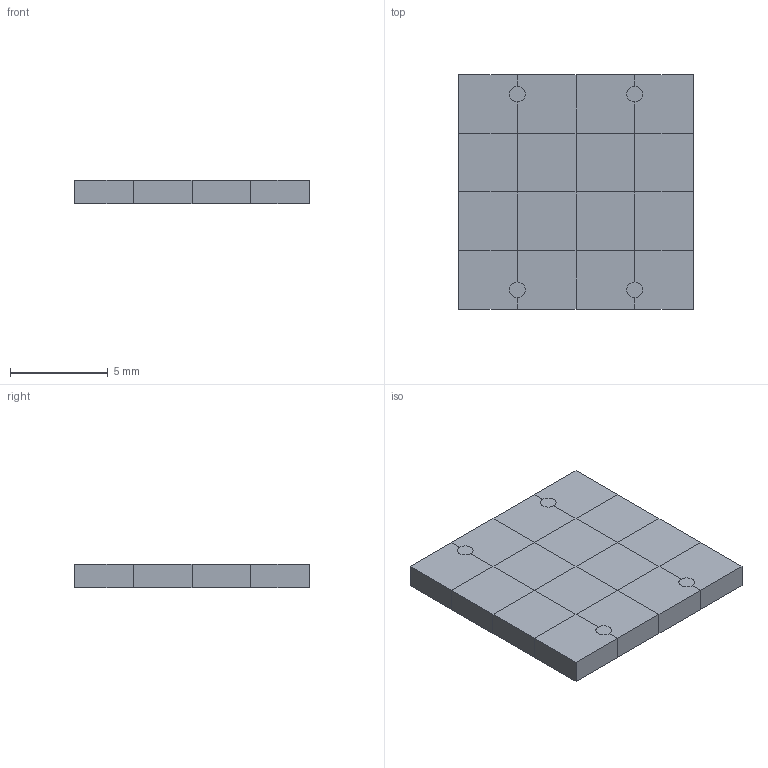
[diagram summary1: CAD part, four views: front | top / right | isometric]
STEP (ISO 10303-21) file: header records copied from the file, then geometry measured from it (millimetres).
FILE_DESCRIPTION(('Open CASCADE Model'),'2;1');
FILE_NAME('Open CASCADE Shape Model','2026-11-27T10:08:37',('Author'),( 'Open CASCADE'),'Open CASCADE STEP processor 7.9','Open CASCADE 7.9' ,'Unknown');
FILE_SCHEMA(('AUTOMOTIVE_DESIGN { 1 0 10303 214 1 1 1 1 }'));
Length unit declared in the file: millimetre
Products named in the file (3): manifold_N19; fluid; solid
Assembly tree (2 placements, depth 2):
  manifold_N19
    fluid
    solid
Bounding box: 12 x 12 x 1.2 mm (x, y, z)
Volume: 172.8 mm3; surface area: 1483.2 mm2
Topology: 2 solids, 2 shells, 1612 faces, 5792 edges, 3214 vertices
Faces by surface type: plane 1604, cylinder 8
Full cylindrical faces by diameter (mm): 0.8 x8
Entity records: 135398 total; most frequent: CARTESIAN_POINT 22253, DIRECTION 20622, LINE 17328, VECTOR 17328, ORIENTED_EDGE 11584, PCURVE 11584, DEFINITIONAL_REPRESENTATION 11584, EDGE_CURVE 5792
One B-rep face of a CAD part: STEP entity #72610.
In plain terms, the planar face has unit normal (0, 0, 1).
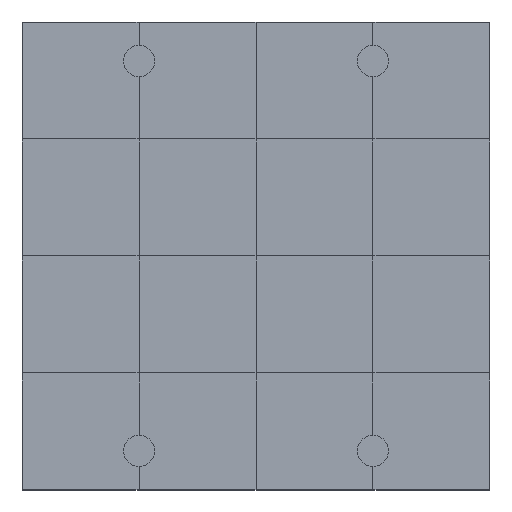
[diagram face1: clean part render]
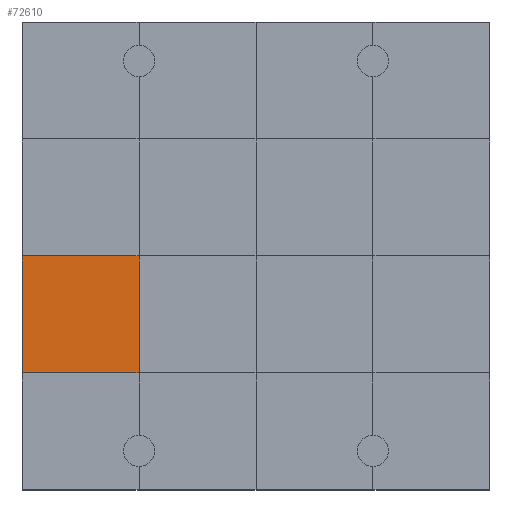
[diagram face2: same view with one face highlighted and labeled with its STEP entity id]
Its self-contained STEP definition (entity closure, numbers rounded to 3 decimals):
#72160 = VERTEX_POINT('',#72161);
#72161 = CARTESIAN_POINT('',(0.,3.,1.2));
#72175 = PLANE('',#72176);
#72176 = AXIS2_PLACEMENT_3D('',#72177,#72178,#72179);
#72177 = CARTESIAN_POINT('',(0.,3.,0.));
#72178 = DIRECTION('',(1.,0.,-0.));
#72179 = DIRECTION('',(0.,0.,1.));
#72201 = PLANE('',#72202);
#72202 = AXIS2_PLACEMENT_3D('',#72203,#72204,#72205);
#72203 = CARTESIAN_POINT('',(0.,0.,1.2));
#72204 = DIRECTION('',(0.,0.,1.));
#72205 = DIRECTION('',(1.,0.,-0.));
#72352 = VERTEX_POINT('',#72353);
#72353 = CARTESIAN_POINT('',(3.,3.,1.2));
#72374 = EDGE_CURVE('',#72160,#72352,#72375,.T.);
#72375 = SURFACE_CURVE('',#72376,(#72380,#72387),.PCURVE_S1.);
#72376 = LINE('',#72377,#72378);
#72377 = CARTESIAN_POINT('',(0.,3.,1.2));
#72378 = VECTOR('',#72379,1.);
#72379 = DIRECTION('',(1.,0.,-0.));
#72380 = PCURVE('',#72201,#72381);
#72381 = DEFINITIONAL_REPRESENTATION('',(#72382),#72386);
#72382 = LINE('',#72383,#72384);
#72383 = CARTESIAN_POINT('',(0.,3.));
#72384 = VECTOR('',#72385,1.);
#72385 = DIRECTION('',(1.,0.));
#72386 = ( GEOMETRIC_REPRESENTATION_CONTEXT(2) 
PARAMETRIC_REPRESENTATION_CONTEXT() REPRESENTATION_CONTEXT('2D SPACE',''
  ) );
#72387 = PCURVE('',#72388,#72393);
#72388 = PLANE('',#72389);
#72389 = AXIS2_PLACEMENT_3D('',#72390,#72391,#72392);
#72390 = CARTESIAN_POINT('',(0.,3.,1.2));
#72391 = DIRECTION('',(0.,0.,1.));
#72392 = DIRECTION('',(1.,0.,-0.));
#72393 = DEFINITIONAL_REPRESENTATION('',(#72394),#72398);
#72394 = LINE('',#72395,#72396);
#72395 = CARTESIAN_POINT('',(0.,0.));
#72396 = VECTOR('',#72397,1.);
#72397 = DIRECTION('',(1.,0.));
#72398 = ( GEOMETRIC_REPRESENTATION_CONTEXT(2) 
PARAMETRIC_REPRESENTATION_CONTEXT() REPRESENTATION_CONTEXT('2D SPACE',''
  ) );
#72433 = VERTEX_POINT('',#72434);
#72434 = CARTESIAN_POINT('',(0.,6.,1.2));
#72460 = EDGE_CURVE('',#72160,#72433,#72461,.T.);
#72461 = SURFACE_CURVE('',#72462,(#72466,#72473),.PCURVE_S1.);
#72462 = LINE('',#72463,#72464);
#72463 = CARTESIAN_POINT('',(0.,3.,1.2));
#72464 = VECTOR('',#72465,1.);
#72465 = DIRECTION('',(-0.,1.,0.));
#72466 = PCURVE('',#72175,#72467);
#72467 = DEFINITIONAL_REPRESENTATION('',(#72468),#72472);
#72468 = LINE('',#72469,#72470);
#72469 = CARTESIAN_POINT('',(1.2,0.));
#72470 = VECTOR('',#72471,1.);
#72471 = DIRECTION('',(0.,-1.));
#72472 = ( GEOMETRIC_REPRESENTATION_CONTEXT(2) 
PARAMETRIC_REPRESENTATION_CONTEXT() REPRESENTATION_CONTEXT('2D SPACE',''
  ) );
#72473 = PCURVE('',#72388,#72474);
#72474 = DEFINITIONAL_REPRESENTATION('',(#72475),#72479);
#72475 = LINE('',#72476,#72477);
#72476 = CARTESIAN_POINT('',(0.,0.));
#72477 = VECTOR('',#72478,1.);
#72478 = DIRECTION('',(0.,1.));
#72479 = ( GEOMETRIC_REPRESENTATION_CONTEXT(2) 
PARAMETRIC_REPRESENTATION_CONTEXT() REPRESENTATION_CONTEXT('2D SPACE',''
  ) );
#72610 = ADVANCED_FACE('',(#72611),#72388,.T.);
#72611 = FACE_BOUND('',#72612,.T.);
#72612 = EDGE_LOOP('',(#72613,#72614,#72615,#72643));
#72613 = ORIENTED_EDGE('',*,*,#72460,.F.);
#72614 = ORIENTED_EDGE('',*,*,#72374,.T.);
#72615 = ORIENTED_EDGE('',*,*,#72616,.T.);
#72616 = EDGE_CURVE('',#72352,#72617,#72619,.T.);
#72617 = VERTEX_POINT('',#72618);
#72618 = CARTESIAN_POINT('',(3.,6.,1.2));
#72619 = SURFACE_CURVE('',#72620,(#72624,#72631),.PCURVE_S1.);
#72620 = LINE('',#72621,#72622);
#72621 = CARTESIAN_POINT('',(3.,3.,1.2));
#72622 = VECTOR('',#72623,1.);
#72623 = DIRECTION('',(-0.,1.,0.));
#72624 = PCURVE('',#72388,#72625);
#72625 = DEFINITIONAL_REPRESENTATION('',(#72626),#72630);
#72626 = LINE('',#72627,#72628);
#72627 = CARTESIAN_POINT('',(3.,0.));
#72628 = VECTOR('',#72629,1.);
#72629 = DIRECTION('',(0.,1.));
#72630 = ( GEOMETRIC_REPRESENTATION_CONTEXT(2) 
PARAMETRIC_REPRESENTATION_CONTEXT() REPRESENTATION_CONTEXT('2D SPACE',''
  ) );
#72631 = PCURVE('',#72632,#72637);
#72632 = PLANE('',#72633);
#72633 = AXIS2_PLACEMENT_3D('',#72634,#72635,#72636);
#72634 = CARTESIAN_POINT('',(3.,3.,1.2));
#72635 = DIRECTION('',(0.,0.,1.));
#72636 = DIRECTION('',(1.,0.,-0.));
#72637 = DEFINITIONAL_REPRESENTATION('',(#72638),#72642);
#72638 = LINE('',#72639,#72640);
#72639 = CARTESIAN_POINT('',(0.,0.));
#72640 = VECTOR('',#72641,1.);
#72641 = DIRECTION('',(0.,1.));
#72642 = ( GEOMETRIC_REPRESENTATION_CONTEXT(2) 
PARAMETRIC_REPRESENTATION_CONTEXT() REPRESENTATION_CONTEXT('2D SPACE',''
  ) );
#72643 = ORIENTED_EDGE('',*,*,#72644,.F.);
#72644 = EDGE_CURVE('',#72433,#72617,#72645,.T.);
#72645 = SURFACE_CURVE('',#72646,(#72650,#72657),.PCURVE_S1.);
#72646 = LINE('',#72647,#72648);
#72647 = CARTESIAN_POINT('',(0.,6.,1.2));
#72648 = VECTOR('',#72649,1.);
#72649 = DIRECTION('',(1.,0.,-0.));
#72650 = PCURVE('',#72388,#72651);
#72651 = DEFINITIONAL_REPRESENTATION('',(#72652),#72656);
#72652 = LINE('',#72653,#72654);
#72653 = CARTESIAN_POINT('',(0.,3.));
#72654 = VECTOR('',#72655,1.);
#72655 = DIRECTION('',(1.,0.));
#72656 = ( GEOMETRIC_REPRESENTATION_CONTEXT(2) 
PARAMETRIC_REPRESENTATION_CONTEXT() REPRESENTATION_CONTEXT('2D SPACE',''
  ) );
#72657 = PCURVE('',#72658,#72663);
#72658 = PLANE('',#72659);
#72659 = AXIS2_PLACEMENT_3D('',#72660,#72661,#72662);
#72660 = CARTESIAN_POINT('',(0.,6.,1.2));
#72661 = DIRECTION('',(0.,0.,1.));
#72662 = DIRECTION('',(1.,0.,-0.));
#72663 = DEFINITIONAL_REPRESENTATION('',(#72664),#72668);
#72664 = LINE('',#72665,#72666);
#72665 = CARTESIAN_POINT('',(0.,0.));
#72666 = VECTOR('',#72667,1.);
#72667 = DIRECTION('',(1.,0.));
#72668 = ( GEOMETRIC_REPRESENTATION_CONTEXT(2) 
PARAMETRIC_REPRESENTATION_CONTEXT() REPRESENTATION_CONTEXT('2D SPACE',''
  ) );
